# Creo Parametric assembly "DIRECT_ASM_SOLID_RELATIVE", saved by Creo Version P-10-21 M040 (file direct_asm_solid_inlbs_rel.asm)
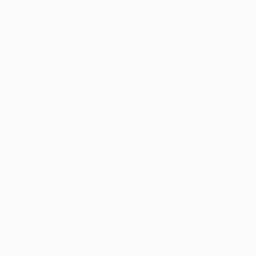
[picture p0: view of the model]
Units: Inch lbm Second (Pro/E Default); INCH, POUND, SECS

Created from: INLBS_ASM_DESIGN.ASM

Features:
  1. datum plane "ASM_RIGHT"
  2. datum plane "ASM_TOP"
  3. datum plane "ASM_FRONT"
  4. coordinate system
